VERSION 5.7 ;
  NOWIREEXTENSIONATPIN ON ;
  DIVIDERCHAR "/" ;
  BUSBITCHARS "[]" ;
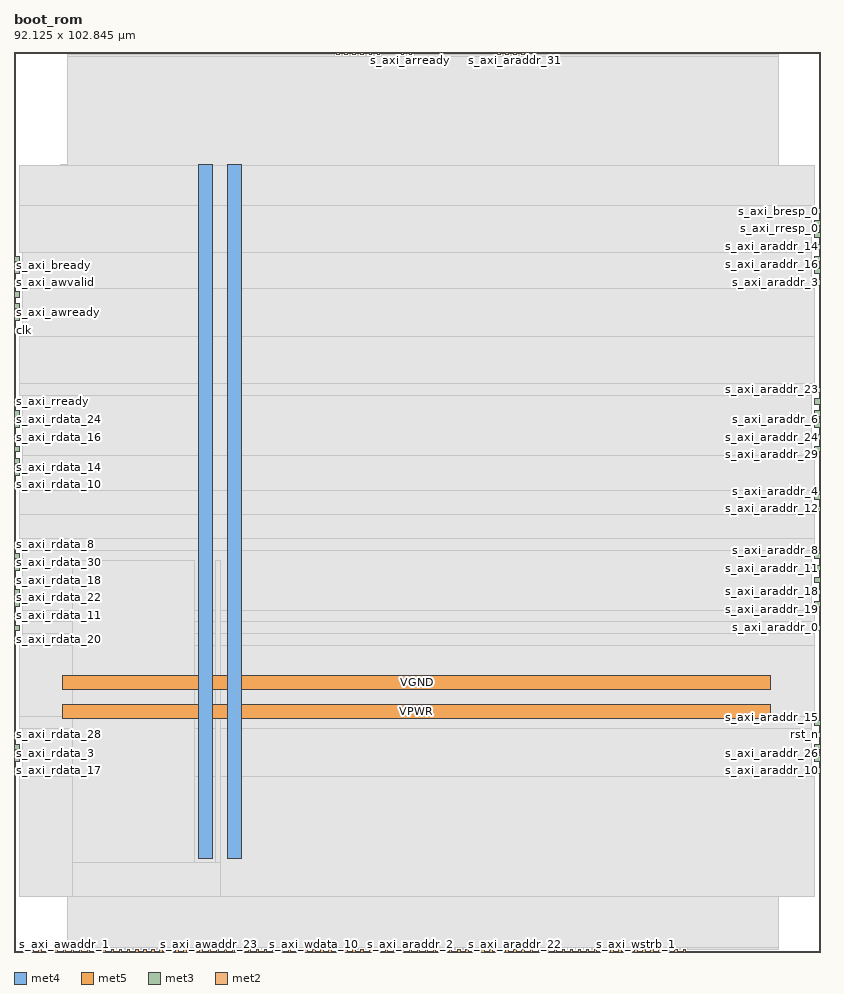
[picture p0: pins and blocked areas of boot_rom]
MACRO boot_rom
  CLASS BLOCK ;
  FOREIGN boot_rom ;
  ORIGIN 0.000 0.000 ;
  SIZE 92.125 BY 102.845 ;
  PIN VGND
    DIRECTION INOUT ;
    USE GROUND ;
    PORT
      LAYER met4 ;
        RECT 24.340 10.640 25.940 90.000 ;
    END
    PORT
      LAYER met5 ;
        RECT 5.520 30.030 86.480 31.630 ;
    END
  END VGND
  PIN VPWR
    DIRECTION INOUT ;
    USE POWER ;
    PORT
      LAYER met4 ;
        RECT 21.040 10.640 22.640 90.000 ;
    END
    PORT
      LAYER met5 ;
        RECT 5.520 26.730 86.480 28.330 ;
    END
  END VPWR
  PIN clk
    DIRECTION INPUT ;
    USE SIGNAL ;
    ANTENNAGATEAREA 1.286700 ;
    ANTENNADIFFAREA 0.434700 ;
    PORT
      LAYER met3 ;
        RECT 0.000 70.760 0.600 71.360 ;
    END
  END clk
  PIN rst_n
    DIRECTION INPUT ;
    USE SIGNAL ;
    ANTENNAGATEAREA 0.647700 ;
    ANTENNADIFFAREA 0.434700 ;
    PORT
      LAYER met3 ;
        RECT 91.525 24.520 92.125 25.120 ;
    END
  END rst_n
  PIN s_axi_araddr_0
    DIRECTION INPUT ;
    USE SIGNAL ;
    ANTENNAGATEAREA 0.647700 ;
    ANTENNADIFFAREA 0.434700 ;
    PORT
      LAYER met3 ;
        RECT 91.525 36.760 92.125 37.360 ;
    END
  END s_axi_araddr_0
  PIN s_axi_araddr_1
    DIRECTION INPUT ;
    USE SIGNAL ;
    ANTENNAGATEAREA 0.647700 ;
    ANTENNADIFFAREA 0.434700 ;
    PORT
      LAYER met2 ;
        RECT 56.210 102.565 56.490 102.845 ;
    END
  END s_axi_araddr_1
  PIN s_axi_araddr_10
    DIRECTION INPUT ;
    USE SIGNAL ;
    ANTENNAGATEAREA 0.647700 ;
    ANTENNADIFFAREA 0.434700 ;
    PORT
      LAYER met3 ;
        RECT 91.525 20.440 92.125 21.040 ;
    END
  END s_axi_araddr_10
  PIN s_axi_araddr_11
    DIRECTION INPUT ;
    USE SIGNAL ;
    ANTENNAGATEAREA 0.647700 ;
    ANTENNADIFFAREA 0.434700 ;
    PORT
      LAYER met3 ;
        RECT 91.525 43.560 92.125 44.160 ;
    END
  END s_axi_araddr_11
  PIN s_axi_araddr_12
    DIRECTION INPUT ;
    USE SIGNAL ;
    ANTENNAGATEAREA 0.647700 ;
    ANTENNADIFFAREA 0.434700 ;
    PORT
      LAYER met3 ;
        RECT 91.525 50.360 92.125 50.960 ;
    END
  END s_axi_araddr_12
  PIN s_axi_araddr_13
    DIRECTION INPUT ;
    USE SIGNAL ;
    ANTENNAGATEAREA 0.647700 ;
    ANTENNADIFFAREA 0.434700 ;
    PORT
      LAYER met2 ;
        RECT 56.210 0.000 56.490 0.280 ;
    END
  END s_axi_araddr_13
  PIN s_axi_araddr_14
    DIRECTION INPUT ;
    USE SIGNAL ;
    ANTENNAGATEAREA 0.647700 ;
    ANTENNADIFFAREA 0.434700 ;
    PORT
      LAYER met3 ;
        RECT 91.525 80.280 92.125 80.880 ;
    END
  END s_axi_araddr_14
  PIN s_axi_araddr_15
    DIRECTION INPUT ;
    USE SIGNAL ;
    ANTENNAGATEAREA 0.647700 ;
    ANTENNADIFFAREA 0.434700 ;
    PORT
      LAYER met3 ;
        RECT 91.525 25.880 92.125 26.480 ;
    END
  END s_axi_araddr_15
  PIN s_axi_araddr_16
    DIRECTION INPUT ;
    USE SIGNAL ;
    ANTENNAGATEAREA 0.647700 ;
    ANTENNADIFFAREA 0.434700 ;
    PORT
      LAYER met3 ;
        RECT 91.525 78.920 92.125 79.520 ;
    END
  END s_axi_araddr_16
  PIN s_axi_araddr_17
    DIRECTION INPUT ;
    USE SIGNAL ;
    ANTENNAGATEAREA 0.647700 ;
    ANTENNADIFFAREA 0.434700 ;
    PORT
      LAYER met2 ;
        RECT 55.290 102.565 55.570 102.845 ;
    END
  END s_axi_araddr_17
  PIN s_axi_araddr_18
    DIRECTION INPUT ;
    USE SIGNAL ;
    ANTENNAGATEAREA 0.647700 ;
    ANTENNADIFFAREA 0.434700 ;
    PORT
      LAYER met3 ;
        RECT 91.525 40.840 92.125 41.440 ;
    END
  END s_axi_araddr_18
  PIN s_axi_araddr_19
    DIRECTION INPUT ;
    USE SIGNAL ;
    ANTENNAGATEAREA 0.647700 ;
    ANTENNADIFFAREA 0.434700 ;
    PORT
      LAYER met3 ;
        RECT 91.525 39.480 92.125 40.080 ;
    END
  END s_axi_araddr_19
  PIN s_axi_araddr_2
    DIRECTION INPUT ;
    USE SIGNAL ;
    ANTENNAGATEAREA 0.647700 ;
    ANTENNADIFFAREA 0.434700 ;
    PORT
      LAYER met2 ;
        RECT 45.170 0.000 45.450 0.280 ;
    END
  END s_axi_araddr_2
  PIN s_axi_araddr_20
    DIRECTION INPUT ;
    USE SIGNAL ;
    ANTENNAGATEAREA 0.647700 ;
    ANTENNADIFFAREA 0.434700 ;
    PORT
      LAYER met3 ;
        RECT 91.525 77.560 92.125 78.160 ;
    END
  END s_axi_araddr_20
  PIN s_axi_araddr_21
    DIRECTION INPUT ;
    USE SIGNAL ;
    ANTENNAGATEAREA 0.647700 ;
    ANTENNADIFFAREA 0.434700 ;
    PORT
      LAYER met3 ;
        RECT 91.525 23.160 92.125 23.760 ;
    END
  END s_axi_araddr_21
  PIN s_axi_araddr_22
    DIRECTION INPUT ;
    USE SIGNAL ;
    ANTENNAGATEAREA 0.647700 ;
    ANTENNADIFFAREA 0.434700 ;
    PORT
      LAYER met2 ;
        RECT 57.130 0.000 57.410 0.280 ;
    END
  END s_axi_araddr_22
  PIN s_axi_araddr_23
    DIRECTION INPUT ;
    USE SIGNAL ;
    ANTENNAGATEAREA 0.647700 ;
    ANTENNADIFFAREA 0.434700 ;
    PORT
      LAYER met3 ;
        RECT 91.525 63.960 92.125 64.560 ;
    END
  END s_axi_araddr_23
  PIN s_axi_araddr_24
    DIRECTION INPUT ;
    USE SIGNAL ;
    ANTENNAGATEAREA 0.647700 ;
    ANTENNADIFFAREA 0.434700 ;
    PORT
      LAYER met3 ;
        RECT 91.525 58.520 92.125 59.120 ;
    END
  END s_axi_araddr_24
  PIN s_axi_araddr_25
    DIRECTION INPUT ;
    USE SIGNAL ;
    ANTENNAGATEAREA 0.647700 ;
    ANTENNADIFFAREA 0.434700 ;
    PORT
      LAYER met2 ;
        RECT 62.650 0.000 62.930 0.280 ;
    END
  END s_axi_araddr_25
  PIN s_axi_araddr_26
    DIRECTION INPUT ;
    USE SIGNAL ;
    ANTENNAGATEAREA 0.647700 ;
    ANTENNADIFFAREA 0.434700 ;
    PORT
      LAYER met3 ;
        RECT 91.525 21.800 92.125 22.400 ;
    END
  END s_axi_araddr_26
  PIN s_axi_araddr_27
    DIRECTION INPUT ;
    USE SIGNAL ;
    ANTENNAGATEAREA 0.647700 ;
    ANTENNADIFFAREA 0.434700 ;
    PORT
      LAYER met3 ;
        RECT 91.525 42.200 92.125 42.800 ;
    END
  END s_axi_araddr_27
  PIN s_axi_araddr_28
    DIRECTION INPUT ;
    USE SIGNAL ;
    ANTENNAGATEAREA 0.647700 ;
    ANTENNADIFFAREA 0.434700 ;
    PORT
      LAYER met2 ;
        RECT 55.290 0.000 55.570 0.280 ;
    END
  END s_axi_araddr_28
  PIN s_axi_araddr_29
    DIRECTION INPUT ;
    USE SIGNAL ;
    ANTENNAGATEAREA 0.647700 ;
    ANTENNADIFFAREA 0.434700 ;
    PORT
      LAYER met3 ;
        RECT 91.525 57.160 92.125 57.760 ;
    END
  END s_axi_araddr_29
  PIN s_axi_araddr_3
    DIRECTION INPUT ;
    USE SIGNAL ;
    ANTENNAGATEAREA 0.647700 ;
    ANTENNADIFFAREA 0.434700 ;
    PORT
      LAYER met3 ;
        RECT 91.525 76.200 92.125 76.800 ;
    END
  END s_axi_araddr_3
  PIN s_axi_araddr_30
    DIRECTION INPUT ;
    USE SIGNAL ;
    ANTENNAGATEAREA 0.647700 ;
    ANTENNADIFFAREA 0.434700 ;
    PORT
      LAYER met3 ;
        RECT 91.525 61.240 92.125 61.840 ;
    END
  END s_axi_araddr_30
  PIN s_axi_araddr_31
    DIRECTION INPUT ;
    USE SIGNAL ;
    ANTENNAGATEAREA 0.647700 ;
    ANTENNADIFFAREA 0.434700 ;
    PORT
      LAYER met2 ;
        RECT 57.130 102.565 57.410 102.845 ;
    END
  END s_axi_araddr_31
  PIN s_axi_araddr_4
    DIRECTION INPUT ;
    USE SIGNAL ;
    ANTENNAGATEAREA 0.647700 ;
    ANTENNADIFFAREA 0.434700 ;
    PORT
      LAYER met3 ;
        RECT 91.525 51.720 92.125 52.320 ;
    END
  END s_axi_araddr_4
  PIN s_axi_araddr_5
    DIRECTION INPUT ;
    USE SIGNAL ;
    ANTENNAGATEAREA 0.647700 ;
    ANTENNADIFFAREA 0.434700 ;
    PORT
      LAYER met2 ;
        RECT 59.890 0.000 60.170 0.280 ;
    END
  END s_axi_araddr_5
  PIN s_axi_araddr_6
    DIRECTION INPUT ;
    USE SIGNAL ;
    ANTENNAGATEAREA 0.647700 ;
    ANTENNADIFFAREA 0.434700 ;
    PORT
      LAYER met3 ;
        RECT 91.525 59.880 92.125 60.480 ;
    END
  END s_axi_araddr_6
  PIN s_axi_araddr_7
    DIRECTION INPUT ;
    USE SIGNAL ;
    ANTENNAGATEAREA 0.647700 ;
    ANTENNADIFFAREA 0.434700 ;
    PORT
      LAYER met3 ;
        RECT 91.525 62.600 92.125 63.200 ;
    END
  END s_axi_araddr_7
  PIN s_axi_araddr_8
    DIRECTION INPUT ;
    USE SIGNAL ;
    ANTENNAGATEAREA 0.647700 ;
    ANTENNADIFFAREA 0.434700 ;
    PORT
      LAYER met3 ;
        RECT 91.525 44.920 92.125 45.520 ;
    END
  END s_axi_araddr_8
  PIN s_axi_araddr_9
    DIRECTION INPUT ;
    USE SIGNAL ;
    ANTENNAGATEAREA 0.647700 ;
    ANTENNADIFFAREA 0.434700 ;
    PORT
      LAYER met2 ;
        RECT 58.050 102.565 58.330 102.845 ;
    END
  END s_axi_araddr_9
  PIN s_axi_arready
    DIRECTION OUTPUT ;
    USE SIGNAL ;
    ANTENNAGATEAREA 0.434700 ;
    ANTENNADIFFAREA 1.137600 ;
    PORT
      LAYER met2 ;
        RECT 45.170 102.565 45.450 102.845 ;
    END
  END s_axi_arready
  PIN s_axi_arvalid
    DIRECTION INPUT ;
    USE SIGNAL ;
    ANTENNAGATEAREA 0.647700 ;
    ANTENNADIFFAREA 0.434700 ;
    PORT
      LAYER met2 ;
        RECT 44.250 102.565 44.530 102.845 ;
    END
  END s_axi_arvalid
  PIN s_axi_awaddr_0
    DIRECTION INPUT ;
    USE SIGNAL ;
    PORT
      LAYER met2 ;
        RECT 2.850 0.000 3.130 0.280 ;
    END
  END s_axi_awaddr_0
  PIN s_axi_awaddr_1
    DIRECTION INPUT ;
    USE SIGNAL ;
    PORT
      LAYER met2 ;
        RECT 5.610 0.000 5.890 0.280 ;
    END
  END s_axi_awaddr_1
  PIN s_axi_awaddr_10
    DIRECTION INPUT ;
    USE SIGNAL ;
    PORT
      LAYER met2 ;
        RECT 4.690 0.000 4.970 0.280 ;
    END
  END s_axi_awaddr_10
  PIN s_axi_awaddr_11
    DIRECTION INPUT ;
    USE SIGNAL ;
    PORT
      LAYER met2 ;
        RECT 7.450 0.000 7.730 0.280 ;
    END
  END s_axi_awaddr_11
  PIN s_axi_awaddr_12
    DIRECTION INPUT ;
    USE SIGNAL ;
    PORT
      LAYER met2 ;
        RECT 6.530 0.000 6.810 0.280 ;
    END
  END s_axi_awaddr_12
  PIN s_axi_awaddr_13
    DIRECTION INPUT ;
    USE SIGNAL ;
    PORT
      LAYER met2 ;
        RECT 28.610 0.000 28.890 0.280 ;
    END
  END s_axi_awaddr_13
  PIN s_axi_awaddr_14
    DIRECTION INPUT ;
    USE SIGNAL ;
    PORT
      LAYER met2 ;
        RECT 8.370 0.000 8.650 0.280 ;
    END
  END s_axi_awaddr_14
  PIN s_axi_awaddr_15
    DIRECTION INPUT ;
    USE SIGNAL ;
    PORT
      LAYER met2 ;
        RECT 9.290 0.000 9.570 0.280 ;
    END
  END s_axi_awaddr_15
  PIN s_axi_awaddr_16
    DIRECTION INPUT ;
    USE SIGNAL ;
    PORT
      LAYER met2 ;
        RECT 10.210 0.000 10.490 0.280 ;
    END
  END s_axi_awaddr_16
  PIN s_axi_awaddr_17
    DIRECTION INPUT ;
    USE SIGNAL ;
    PORT
      LAYER met2 ;
        RECT 11.130 0.000 11.410 0.280 ;
    END
  END s_axi_awaddr_17
  PIN s_axi_awaddr_18
    DIRECTION INPUT ;
    USE SIGNAL ;
    PORT
      LAYER met2 ;
        RECT 12.050 0.000 12.330 0.280 ;
    END
  END s_axi_awaddr_18
  PIN s_axi_awaddr_19
    DIRECTION INPUT ;
    USE SIGNAL ;
    PORT
      LAYER met2 ;
        RECT 12.970 0.000 13.250 0.280 ;
    END
  END s_axi_awaddr_19
  PIN s_axi_awaddr_2
    DIRECTION INPUT ;
    USE SIGNAL ;
    PORT
      LAYER met2 ;
        RECT 13.890 0.000 14.170 0.280 ;
    END
  END s_axi_awaddr_2
  PIN s_axi_awaddr_20
    DIRECTION INPUT ;
    USE SIGNAL ;
    PORT
      LAYER met2 ;
        RECT 46.090 0.000 46.370 0.280 ;
    END
  END s_axi_awaddr_20
  PIN s_axi_awaddr_21
    DIRECTION INPUT ;
    USE SIGNAL ;
    PORT
      LAYER met2 ;
        RECT 14.810 0.000 15.090 0.280 ;
    END
  END s_axi_awaddr_21
  PIN s_axi_awaddr_22
    DIRECTION INPUT ;
    USE SIGNAL ;
    PORT
      LAYER met2 ;
        RECT 15.730 0.000 16.010 0.280 ;
    END
  END s_axi_awaddr_22
  PIN s_axi_awaddr_23
    DIRECTION INPUT ;
    USE SIGNAL ;
    PORT
      LAYER met2 ;
        RECT 22.170 0.000 22.450 0.280 ;
    END
  END s_axi_awaddr_23
  PIN s_axi_awaddr_24
    DIRECTION INPUT ;
    USE SIGNAL ;
    PORT
      LAYER met2 ;
        RECT 1.930 0.000 2.210 0.280 ;
    END
  END s_axi_awaddr_24
  PIN s_axi_awaddr_25
    DIRECTION INPUT ;
    USE SIGNAL ;
    PORT
      LAYER met2 ;
        RECT 18.490 0.000 18.770 0.280 ;
    END
  END s_axi_awaddr_25
  PIN s_axi_awaddr_26
    DIRECTION INPUT ;
    USE SIGNAL ;
    PORT
      LAYER met2 ;
        RECT 19.410 0.000 19.690 0.280 ;
    END
  END s_axi_awaddr_26
  PIN s_axi_awaddr_27
    DIRECTION INPUT ;
    USE SIGNAL ;
    PORT
      LAYER met2 ;
        RECT 20.330 0.000 20.610 0.280 ;
    END
  END s_axi_awaddr_27
  PIN s_axi_awaddr_28
    DIRECTION INPUT ;
    USE SIGNAL ;
    PORT
      LAYER met2 ;
        RECT 21.250 0.000 21.530 0.280 ;
    END
  END s_axi_awaddr_28
  PIN s_axi_awaddr_29
    DIRECTION INPUT ;
    USE SIGNAL ;
    PORT
      LAYER met2 ;
        RECT 27.690 0.000 27.970 0.280 ;
    END
  END s_axi_awaddr_29
  PIN s_axi_awaddr_3
    DIRECTION INPUT ;
    USE SIGNAL ;
    PORT
      LAYER met2 ;
        RECT 23.090 0.000 23.370 0.280 ;
    END
  END s_axi_awaddr_3
  PIN s_axi_awaddr_30
    DIRECTION INPUT ;
    USE SIGNAL ;
    PORT
      LAYER met2 ;
        RECT 24.010 0.000 24.290 0.280 ;
    END
  END s_axi_awaddr_30
  PIN s_axi_awaddr_31
    DIRECTION INPUT ;
    USE SIGNAL ;
    PORT
      LAYER met2 ;
        RECT 24.930 0.000 25.210 0.280 ;
    END
  END s_axi_awaddr_31
  PIN s_axi_awaddr_4
    DIRECTION INPUT ;
    USE SIGNAL ;
    PORT
      LAYER met2 ;
        RECT 25.850 0.000 26.130 0.280 ;
    END
  END s_axi_awaddr_4
  PIN s_axi_awaddr_5
    DIRECTION INPUT ;
    USE SIGNAL ;
    PORT
      LAYER met2 ;
        RECT 26.770 0.000 27.050 0.280 ;
    END
  END s_axi_awaddr_5
  PIN s_axi_awaddr_6
    DIRECTION INPUT ;
    USE SIGNAL ;
    PORT
      LAYER met2 ;
        RECT 33.210 0.000 33.490 0.280 ;
    END
  END s_axi_awaddr_6
  PIN s_axi_awaddr_7
    DIRECTION INPUT ;
    USE SIGNAL ;
    PORT
      LAYER met2 ;
        RECT 54.370 0.000 54.650 0.280 ;
    END
  END s_axi_awaddr_7
  PIN s_axi_awaddr_8
    DIRECTION INPUT ;
    USE SIGNAL ;
    PORT
      LAYER met2 ;
        RECT 29.530 0.000 29.810 0.280 ;
    END
  END s_axi_awaddr_8
  PIN s_axi_awaddr_9
    DIRECTION INPUT ;
    USE SIGNAL ;
    PORT
      LAYER met2 ;
        RECT 30.450 0.000 30.730 0.280 ;
    END
  END s_axi_awaddr_9
  PIN s_axi_awready
    DIRECTION OUTPUT ;
    USE SIGNAL ;
    ANTENNAGATEAREA 0.434700 ;
    ANTENNADIFFAREA 1.137600 ;
    PORT
      LAYER met3 ;
        RECT 0.000 72.120 0.600 72.720 ;
    END
  END s_axi_awready
  PIN s_axi_awvalid
    DIRECTION INPUT ;
    USE SIGNAL ;
    ANTENNAGATEAREA 0.647700 ;
    ANTENNADIFFAREA 0.434700 ;
    PORT
      LAYER met3 ;
        RECT 0.000 76.200 0.600 76.800 ;
    END
  END s_axi_awvalid
  PIN s_axi_bready
    DIRECTION INPUT ;
    USE SIGNAL ;
    ANTENNAGATEAREA 0.647700 ;
    ANTENNADIFFAREA 0.434700 ;
    PORT
      LAYER met3 ;
        RECT 0.000 77.560 0.600 78.160 ;
    END
  END s_axi_bready
  PIN s_axi_bresp_0
    DIRECTION OUTPUT ;
    USE SIGNAL ;
    ANTENNAGATEAREA 0.434700 ;
    ANTENNADIFFAREA 0.434700 ;
    PORT
      LAYER met3 ;
        RECT 91.525 84.360 92.125 84.960 ;
    END
  END s_axi_bresp_0
  PIN s_axi_bresp_1
    DIRECTION OUTPUT ;
    USE SIGNAL ;
    PORT
      LAYER met2 ;
        RECT 31.370 0.000 31.650 0.280 ;
    END
  END s_axi_bresp_1
  PIN s_axi_bvalid
    DIRECTION OUTPUT ;
    USE SIGNAL ;
    ANTENNAGATEAREA 0.434700 ;
    ANTENNADIFFAREA 1.137600 ;
    PORT
      LAYER met3 ;
        RECT 0.000 78.920 0.600 79.520 ;
    END
  END s_axi_bvalid
  PIN s_axi_rdata_0
    DIRECTION OUTPUT ;
    USE SIGNAL ;
    ANTENNAGATEAREA 0.434700 ;
    ANTENNADIFFAREA 1.137600 ;
    PORT
      LAYER met2 ;
        RECT 37.810 102.565 38.090 102.845 ;
    END
  END s_axi_rdata_0
  PIN s_axi_rdata_1
    DIRECTION OUTPUT ;
    USE SIGNAL ;
    ANTENNAGATEAREA 0.434700 ;
    ANTENNADIFFAREA 1.137600 ;
    PORT
      LAYER met2 ;
        RECT 39.650 102.565 39.930 102.845 ;
    END
  END s_axi_rdata_1
  PIN s_axi_rdata_10
    DIRECTION OUTPUT ;
    USE SIGNAL ;
    ANTENNAGATEAREA 0.434700 ;
    ANTENNADIFFAREA 1.137600 ;
    PORT
      LAYER met3 ;
        RECT 0.000 53.080 0.600 53.680 ;
    END
  END s_axi_rdata_10
  PIN s_axi_rdata_11
    DIRECTION OUTPUT ;
    USE SIGNAL ;
    ANTENNAGATEAREA 0.434700 ;
    ANTENNADIFFAREA 1.137600 ;
    PORT
      LAYER met3 ;
        RECT 0.000 38.120 0.600 38.720 ;
    END
  END s_axi_rdata_11
  PIN s_axi_rdata_12
    DIRECTION OUTPUT ;
    USE SIGNAL ;
    ANTENNAGATEAREA 0.434700 ;
    ANTENNADIFFAREA 1.137600 ;
    PORT
      LAYER met2 ;
        RECT 16.650 0.000 16.930 0.280 ;
    END
  END s_axi_rdata_12
  PIN s_axi_rdata_13
    DIRECTION OUTPUT ;
    USE SIGNAL ;
    ANTENNAGATEAREA 0.434700 ;
    ANTENNADIFFAREA 1.137600 ;
    PORT
      LAYER met3 ;
        RECT 0.000 61.240 0.600 61.840 ;
    END
  END s_axi_rdata_13
  PIN s_axi_rdata_14
    DIRECTION OUTPUT ;
    USE SIGNAL ;
    ANTENNAGATEAREA 0.434700 ;
    ANTENNADIFFAREA 1.137600 ;
    PORT
      LAYER met3 ;
        RECT 0.000 54.440 0.600 55.040 ;
    END
  END s_axi_rdata_14
  PIN s_axi_rdata_15
    DIRECTION OUTPUT ;
    USE SIGNAL ;
    ANTENNAGATEAREA 0.434700 ;
    ANTENNADIFFAREA 1.137600 ;
    PORT
      LAYER met2 ;
        RECT 38.730 0.000 39.010 0.280 ;
    END
  END s_axi_rdata_15
  PIN s_axi_rdata_16
    DIRECTION OUTPUT ;
    USE SIGNAL ;
    ANTENNAGATEAREA 0.434700 ;
    ANTENNADIFFAREA 1.137600 ;
    PORT
      LAYER met3 ;
        RECT 0.000 58.520 0.600 59.120 ;
    END
  END s_axi_rdata_16
  PIN s_axi_rdata_17
    DIRECTION OUTPUT ;
    USE SIGNAL ;
    ANTENNAGATEAREA 0.434700 ;
    ANTENNADIFFAREA 1.137600 ;
    PORT
      LAYER met3 ;
        RECT 0.000 20.440 0.600 21.040 ;
    END
  END s_axi_rdata_17
  PIN s_axi_rdata_18
    DIRECTION OUTPUT ;
    USE SIGNAL ;
    ANTENNAGATEAREA 0.434700 ;
    ANTENNADIFFAREA 1.137600 ;
    PORT
      LAYER met3 ;
        RECT 0.000 42.200 0.600 42.800 ;
    END
  END s_axi_rdata_18
  PIN s_axi_rdata_19
    DIRECTION OUTPUT ;
    USE SIGNAL ;
    ANTENNAGATEAREA 0.434700 ;
    ANTENNADIFFAREA 1.137600 ;
    PORT
      LAYER met2 ;
        RECT 40.570 0.000 40.850 0.280 ;
    END
  END s_axi_rdata_19
  PIN s_axi_rdata_2
    DIRECTION OUTPUT ;
    USE SIGNAL ;
    ANTENNAGATEAREA 0.434700 ;
    ANTENNADIFFAREA 1.137600 ;
    PORT
      LAYER met2 ;
        RECT 38.730 102.565 39.010 102.845 ;
    END
  END s_axi_rdata_2
  PIN s_axi_rdata_20
    DIRECTION OUTPUT ;
    USE SIGNAL ;
    ANTENNAGATEAREA 0.434700 ;
    ANTENNADIFFAREA 1.137600 ;
    PORT
      LAYER met3 ;
        RECT 0.000 35.400 0.600 36.000 ;
    END
  END s_axi_rdata_20
  PIN s_axi_rdata_21
    DIRECTION OUTPUT ;
    USE SIGNAL ;
    ANTENNAGATEAREA 0.434700 ;
    ANTENNADIFFAREA 1.137600 ;
    PORT
      LAYER met3 ;
        RECT 0.000 57.160 0.600 57.760 ;
    END
  END s_axi_rdata_21
  PIN s_axi_rdata_22
    DIRECTION OUTPUT ;
    USE SIGNAL ;
    ANTENNAGATEAREA 0.434700 ;
    ANTENNADIFFAREA 1.137600 ;
    PORT
      LAYER met3 ;
        RECT 0.000 40.840 0.600 41.440 ;
    END
  END s_axi_rdata_22
  PIN s_axi_rdata_23
    DIRECTION OUTPUT ;
    USE SIGNAL ;
    ANTENNAGATEAREA 0.434700 ;
    ANTENNADIFFAREA 1.137600 ;
    PORT
      LAYER met2 ;
        RECT 17.570 0.000 17.850 0.280 ;
    END
  END s_axi_rdata_23
  PIN s_axi_rdata_24
    DIRECTION OUTPUT ;
    USE SIGNAL ;
    ANTENNAGATEAREA 0.434700 ;
    ANTENNADIFFAREA 1.137600 ;
    PORT
      LAYER met3 ;
        RECT 0.000 59.880 0.600 60.480 ;
    END
  END s_axi_rdata_24
  PIN s_axi_rdata_25
    DIRECTION OUTPUT ;
    USE SIGNAL ;
    ANTENNAGATEAREA 0.434700 ;
    ANTENNADIFFAREA 1.137600 ;
    PORT
      LAYER met3 ;
        RECT 0.000 39.480 0.600 40.080 ;
    END
  END s_axi_rdata_25
  PIN s_axi_rdata_26
    DIRECTION OUTPUT ;
    USE SIGNAL ;
    ANTENNAGATEAREA 0.434700 ;
    ANTENNADIFFAREA 1.137600 ;
    PORT
      LAYER met3 ;
        RECT 0.000 44.920 0.600 45.520 ;
    END
  END s_axi_rdata_26
  PIN s_axi_rdata_27
    DIRECTION OUTPUT ;
    USE SIGNAL ;
    ANTENNAGATEAREA 0.434700 ;
    ANTENNADIFFAREA 1.137600 ;
    PORT
      LAYER met3 ;
        RECT 0.000 55.800 0.600 56.400 ;
    END
  END s_axi_rdata_27
  PIN s_axi_rdata_28
    DIRECTION OUTPUT ;
    USE SIGNAL ;
    ANTENNAGATEAREA 0.434700 ;
    ANTENNADIFFAREA 1.137600 ;
    PORT
      LAYER met3 ;
        RECT 0.000 24.520 0.600 25.120 ;
    END
  END s_axi_rdata_28
  PIN s_axi_rdata_29
    DIRECTION OUTPUT ;
    USE SIGNAL ;
    ANTENNAGATEAREA 0.434700 ;
    ANTENNADIFFAREA 1.137600 ;
    PORT
      LAYER met2 ;
        RECT 37.810 0.000 38.090 0.280 ;
    END
  END s_axi_rdata_29
  PIN s_axi_rdata_3
    DIRECTION OUTPUT ;
    USE SIGNAL ;
    ANTENNAGATEAREA 0.434700 ;
    ANTENNADIFFAREA 1.137600 ;
    PORT
      LAYER met3 ;
        RECT 0.000 21.800 0.600 22.400 ;
    END
  END s_axi_rdata_3
  PIN s_axi_rdata_30
    DIRECTION OUTPUT ;
    USE SIGNAL ;
    ANTENNAGATEAREA 0.434700 ;
    ANTENNADIFFAREA 1.137600 ;
    PORT
      LAYER met3 ;
        RECT 0.000 43.560 0.600 44.160 ;
    END
  END s_axi_rdata_30
  PIN s_axi_rdata_31
    DIRECTION OUTPUT ;
    USE SIGNAL ;
    ANTENNAGATEAREA 0.434700 ;
    ANTENNADIFFAREA 1.137600 ;
    PORT
      LAYER met3 ;
        RECT 0.000 23.160 0.600 23.760 ;
    END
  END s_axi_rdata_31
  PIN s_axi_rdata_4
    DIRECTION OUTPUT ;
    USE SIGNAL ;
    ANTENNAGATEAREA 0.434700 ;
    ANTENNADIFFAREA 1.137600 ;
    PORT
      LAYER met2 ;
        RECT 36.890 0.000 37.170 0.280 ;
    END
  END s_axi_rdata_4
  PIN s_axi_rdata_5
    DIRECTION OUTPUT ;
    USE SIGNAL ;
    ANTENNAGATEAREA 0.434700 ;
    ANTENNADIFFAREA 1.137600 ;
    PORT
      LAYER met2 ;
        RECT 40.570 102.565 40.850 102.845 ;
    END
  END s_axi_rdata_5
  PIN s_axi_rdata_6
    DIRECTION OUTPUT ;
    USE SIGNAL ;
    ANTENNAGATEAREA 0.434700 ;
    ANTENNADIFFAREA 1.137600 ;
    PORT
      LAYER met2 ;
        RECT 39.650 0.000 39.930 0.280 ;
    END
  END s_axi_rdata_6
  PIN s_axi_rdata_7
    DIRECTION OUTPUT ;
    USE SIGNAL ;
    ANTENNAGATEAREA 0.434700 ;
    ANTENNADIFFAREA 1.137600 ;
    PORT
      LAYER met2 ;
        RECT 41.490 102.565 41.770 102.845 ;
    END
  END s_axi_rdata_7
  PIN s_axi_rdata_8
    DIRECTION OUTPUT ;
    USE SIGNAL ;
    ANTENNAGATEAREA 0.434700 ;
    ANTENNADIFFAREA 1.137600 ;
    PORT
      LAYER met3 ;
        RECT 0.000 46.280 0.600 46.880 ;
    END
  END s_axi_rdata_8
  PIN s_axi_rdata_9
    DIRECTION OUTPUT ;
    USE SIGNAL ;
    ANTENNAGATEAREA 0.434700 ;
    ANTENNADIFFAREA 1.137600 ;
    PORT
      LAYER met3 ;
        RECT 0.000 36.760 0.600 37.360 ;
    END
  END s_axi_rdata_9
  PIN s_axi_rready
    DIRECTION INPUT ;
    USE SIGNAL ;
    ANTENNAGATEAREA 0.647700 ;
    ANTENNADIFFAREA 0.434700 ;
    PORT
      LAYER met3 ;
        RECT 0.000 62.600 0.600 63.200 ;
    END
  END s_axi_rready
  PIN s_axi_rresp_0
    DIRECTION OUTPUT ;
    USE SIGNAL ;
    ANTENNAGATEAREA 0.434700 ;
    ANTENNADIFFAREA 0.775300 ;
    PORT
      LAYER met3 ;
        RECT 91.525 83.000 92.125 83.600 ;
    END
  END s_axi_rresp_0
  PIN s_axi_rresp_1
    DIRECTION OUTPUT ;
    USE SIGNAL ;
    ANTENNAGATEAREA 0.434700 ;
    ANTENNADIFFAREA 0.775300 ;
    PORT
      LAYER met3 ;
        RECT 91.525 81.640 92.125 82.240 ;
    END
  END s_axi_rresp_1
  PIN s_axi_rvalid
    DIRECTION OUTPUT ;
    USE SIGNAL ;
    ANTENNAGATEAREA 0.434700 ;
    ANTENNADIFFAREA 1.137600 ;
    PORT
      LAYER met2 ;
        RECT 36.890 102.565 37.170 102.845 ;
    END
  END s_axi_rvalid
  PIN s_axi_wdata_0
    DIRECTION INPUT ;
    USE SIGNAL ;
    PORT
      LAYER met2 ;
        RECT 32.290 0.000 32.570 0.280 ;
    END
  END s_axi_wdata_0
  PIN s_axi_wdata_1
    DIRECTION INPUT ;
    USE SIGNAL ;
    PORT
      LAYER met2 ;
        RECT 42.410 0.000 42.690 0.280 ;
    END
  END s_axi_wdata_1
  PIN s_axi_wdata_10
    DIRECTION INPUT ;
    USE SIGNAL ;
    PORT
      LAYER met2 ;
        RECT 34.130 0.000 34.410 0.280 ;
    END
  END s_axi_wdata_10
  PIN s_axi_wdata_11
    DIRECTION INPUT ;
    USE SIGNAL ;
    PORT
      LAYER met2 ;
        RECT 35.050 0.000 35.330 0.280 ;
    END
  END s_axi_wdata_11
  PIN s_axi_wdata_12
    DIRECTION INPUT ;
    USE SIGNAL ;
    PORT
      LAYER met2 ;
        RECT 35.970 0.000 36.250 0.280 ;
    END
  END s_axi_wdata_12
  PIN s_axi_wdata_13
    DIRECTION INPUT ;
    USE SIGNAL ;
    PORT
      LAYER met2 ;
        RECT 76.450 0.000 76.730 0.280 ;
    END
  END s_axi_wdata_13
  PIN s_axi_wdata_14
    DIRECTION INPUT ;
    USE SIGNAL ;
    PORT
      LAYER met2 ;
        RECT 41.490 0.000 41.770 0.280 ;
    END
  END s_axi_wdata_14
  PIN s_axi_wdata_15
    DIRECTION INPUT ;
    USE SIGNAL ;
    PORT
      LAYER met2 ;
        RECT 47.930 0.000 48.210 0.280 ;
    END
  END s_axi_wdata_15
  PIN s_axi_wdata_16
    DIRECTION INPUT ;
    USE SIGNAL ;
    PORT
      LAYER met2 ;
        RECT 43.330 0.000 43.610 0.280 ;
    END
  END s_axi_wdata_16
  PIN s_axi_wdata_17
    DIRECTION INPUT ;
    USE SIGNAL ;
    PORT
      LAYER met2 ;
        RECT 44.250 0.000 44.530 0.280 ;
    END
  END s_axi_wdata_17
  PIN s_axi_wdata_18
    DIRECTION INPUT ;
    USE SIGNAL ;
    PORT
      LAYER met2 ;
        RECT 74.610 0.000 74.890 0.280 ;
    END
  END s_axi_wdata_18
  PIN s_axi_wdata_19
    DIRECTION INPUT ;
    USE SIGNAL ;
    PORT
      LAYER met2 ;
        RECT 47.010 0.000 47.290 0.280 ;
    END
  END s_axi_wdata_19
  PIN s_axi_wdata_2
    DIRECTION INPUT ;
    USE SIGNAL ;
    PORT
      LAYER met2 ;
        RECT 52.530 0.000 52.810 0.280 ;
    END
  END s_axi_wdata_2
  PIN s_axi_wdata_20
    DIRECTION INPUT ;
    USE SIGNAL ;
    PORT
      LAYER met2 ;
        RECT 48.850 0.000 49.130 0.280 ;
    END
  END s_axi_wdata_20
  PIN s_axi_wdata_21
    DIRECTION INPUT ;
    USE SIGNAL ;
    PORT
      LAYER met2 ;
        RECT 49.770 0.000 50.050 0.280 ;
    END
  END s_axi_wdata_21
  PIN s_axi_wdata_22
    DIRECTION INPUT ;
    USE SIGNAL ;
    PORT
      LAYER met2 ;
        RECT 50.690 0.000 50.970 0.280 ;
    END
  END s_axi_wdata_22
  PIN s_axi_wdata_23
    DIRECTION INPUT ;
    USE SIGNAL ;
    PORT
      LAYER met2 ;
        RECT 51.610 0.000 51.890 0.280 ;
    END
  END s_axi_wdata_23
  PIN s_axi_wdata_24
    DIRECTION INPUT ;
    USE SIGNAL ;
    PORT
      LAYER met2 ;
        RECT 58.050 0.000 58.330 0.280 ;
    END
  END s_axi_wdata_24
  PIN s_axi_wdata_25
    DIRECTION INPUT ;
    USE SIGNAL ;
    PORT
      LAYER met2 ;
        RECT 53.450 0.000 53.730 0.280 ;
    END
  END s_axi_wdata_25
  PIN s_axi_wdata_26
    DIRECTION INPUT ;
    USE SIGNAL ;
    PORT
      LAYER met2 ;
        RECT 75.530 0.000 75.810 0.280 ;
    END
  END s_axi_wdata_26
  PIN s_axi_wdata_27
    DIRECTION INPUT ;
    USE SIGNAL ;
    PORT
      LAYER met2 ;
        RECT 3.770 0.000 4.050 0.280 ;
    END
  END s_axi_wdata_27
  PIN s_axi_wdata_28
    DIRECTION INPUT ;
    USE SIGNAL ;
    PORT
      LAYER met2 ;
        RECT 61.730 0.000 62.010 0.280 ;
    END
  END s_axi_wdata_28
  PIN s_axi_wdata_29
    DIRECTION INPUT ;
    USE SIGNAL ;
    PORT
      LAYER met2 ;
        RECT 58.970 0.000 59.250 0.280 ;
    END
  END s_axi_wdata_29
  PIN s_axi_wdata_3
    DIRECTION INPUT ;
    USE SIGNAL ;
    PORT
      LAYER met2 ;
        RECT 60.810 0.000 61.090 0.280 ;
    END
  END s_axi_wdata_3
  PIN s_axi_wdata_30
    DIRECTION INPUT ;
    USE SIGNAL ;
    PORT
      LAYER met2 ;
        RECT 64.490 0.000 64.770 0.280 ;
    END
  END s_axi_wdata_30
  PIN s_axi_wdata_31
    DIRECTION INPUT ;
    USE SIGNAL ;
    PORT
      LAYER met2 ;
        RECT 63.570 0.000 63.850 0.280 ;
    END
  END s_axi_wdata_31
  PIN s_axi_wdata_4
    DIRECTION INPUT ;
    USE SIGNAL ;
    PORT
      LAYER met2 ;
        RECT 66.330 0.000 66.610 0.280 ;
    END
  END s_axi_wdata_4
  PIN s_axi_wdata_5
    DIRECTION INPUT ;
    USE SIGNAL ;
    PORT
      LAYER met2 ;
        RECT 65.410 0.000 65.690 0.280 ;
    END
  END s_axi_wdata_5
  PIN s_axi_wdata_6
    DIRECTION INPUT ;
    USE SIGNAL ;
    PORT
      LAYER met2 ;
        RECT 68.170 0.000 68.450 0.280 ;
    END
  END s_axi_wdata_6
  PIN s_axi_wdata_7
    DIRECTION INPUT ;
    USE SIGNAL ;
    PORT
      LAYER met2 ;
        RECT 67.250 0.000 67.530 0.280 ;
    END
  END s_axi_wdata_7
  PIN s_axi_wdata_8
    DIRECTION INPUT ;
    USE SIGNAL ;
    PORT
      LAYER met2 ;
        RECT 70.010 0.000 70.290 0.280 ;
    END
  END s_axi_wdata_8
  PIN s_axi_wdata_9
    DIRECTION INPUT ;
    USE SIGNAL ;
    PORT
      LAYER met2 ;
        RECT 69.090 0.000 69.370 0.280 ;
    END
  END s_axi_wdata_9
  PIN s_axi_wready
    DIRECTION OUTPUT ;
    USE SIGNAL ;
    ANTENNAGATEAREA 0.434700 ;
    ANTENNADIFFAREA 1.137600 ;
    PORT
      LAYER met3 ;
        RECT 0.000 73.480 0.600 74.080 ;
    END
  END s_axi_wready
  PIN s_axi_wstrb_0
    DIRECTION INPUT ;
    USE SIGNAL ;
    PORT
      LAYER met2 ;
        RECT 71.850 0.000 72.130 0.280 ;
    END
  END s_axi_wstrb_0
  PIN s_axi_wstrb_1
    DIRECTION INPUT ;
    USE SIGNAL ;
    PORT
      LAYER met2 ;
        RECT 70.930 0.000 71.210 0.280 ;
    END
  END s_axi_wstrb_1
  PIN s_axi_wstrb_2
    DIRECTION INPUT ;
    USE SIGNAL ;
    PORT
      LAYER met2 ;
        RECT 73.690 0.000 73.970 0.280 ;
    END
  END s_axi_wstrb_2
  PIN s_axi_wstrb_3
    DIRECTION INPUT ;
    USE SIGNAL ;
    PORT
      LAYER met2 ;
        RECT 72.770 0.000 73.050 0.280 ;
    END
  END s_axi_wstrb_3
  PIN s_axi_wvalid
    DIRECTION INPUT ;
    USE SIGNAL ;
    ANTENNAGATEAREA 0.647700 ;
    ANTENNADIFFAREA 0.434700 ;
    PORT
      LAYER met3 ;
        RECT 0.000 74.840 0.600 75.440 ;
    END
  END s_axi_wvalid
  OBS
      LAYER nwell ;
        RECT 5.330 10.795 86.670 89.950 ;
      LAYER li1 ;
        RECT 5.520 10.795 86.480 89.845 ;
      LAYER met1 ;
        RECT 5.520 8.200 87.330 90.000 ;
      LAYER met2 ;
        RECT 6.070 102.285 36.610 102.565 ;
        RECT 37.450 102.285 37.530 102.565 ;
        RECT 38.370 102.285 38.450 102.565 ;
        RECT 39.290 102.285 39.370 102.565 ;
        RECT 40.210 102.285 40.290 102.565 ;
        RECT 41.130 102.285 41.210 102.565 ;
        RECT 42.050 102.285 43.970 102.565 ;
        RECT 44.810 102.285 44.890 102.565 ;
        RECT 45.730 102.285 55.010 102.565 ;
        RECT 55.850 102.285 55.930 102.565 ;
        RECT 56.770 102.285 56.850 102.565 ;
        RECT 57.690 102.285 57.770 102.565 ;
        RECT 58.610 102.285 87.310 102.565 ;
        RECT 6.070 0.560 87.310 102.285 ;
        RECT 6.170 0.280 6.250 0.560 ;
        RECT 7.090 0.280 7.170 0.560 ;
        RECT 8.010 0.280 8.090 0.560 ;
        RECT 8.930 0.280 9.010 0.560 ;
        RECT 9.850 0.280 9.930 0.560 ;
        RECT 10.770 0.280 10.850 0.560 ;
        RECT 11.690 0.280 11.770 0.560 ;
        RECT 12.610 0.280 12.690 0.560 ;
        RECT 13.530 0.280 13.610 0.560 ;
        RECT 14.450 0.280 14.530 0.560 ;
        RECT 15.370 0.280 15.450 0.560 ;
        RECT 16.290 0.280 16.370 0.560 ;
        RECT 17.210 0.280 17.290 0.560 ;
        RECT 18.130 0.280 18.210 0.560 ;
        RECT 19.050 0.280 19.130 0.560 ;
        RECT 19.970 0.280 20.050 0.560 ;
        RECT 20.890 0.280 20.970 0.560 ;
        RECT 21.810 0.280 21.890 0.560 ;
        RECT 22.730 0.280 22.810 0.560 ;
        RECT 23.650 0.280 23.730 0.560 ;
        RECT 24.570 0.280 24.650 0.560 ;
        RECT 25.490 0.280 25.570 0.560 ;
        RECT 26.410 0.280 26.490 0.560 ;
        RECT 27.330 0.280 27.410 0.560 ;
        RECT 28.250 0.280 28.330 0.560 ;
        RECT 29.170 0.280 29.250 0.560 ;
        RECT 30.090 0.280 30.170 0.560 ;
        RECT 31.010 0.280 31.090 0.560 ;
        RECT 31.930 0.280 32.010 0.560 ;
        RECT 32.850 0.280 32.930 0.560 ;
        RECT 33.770 0.280 33.850 0.560 ;
        RECT 34.690 0.280 34.770 0.560 ;
        RECT 35.610 0.280 35.690 0.560 ;
        RECT 36.530 0.280 36.610 0.560 ;
        RECT 37.450 0.280 37.530 0.560 ;
        RECT 38.370 0.280 38.450 0.560 ;
        RECT 39.290 0.280 39.370 0.560 ;
        RECT 40.210 0.280 40.290 0.560 ;
        RECT 41.130 0.280 41.210 0.560 ;
        RECT 42.050 0.280 42.130 0.560 ;
        RECT 42.970 0.280 43.050 0.560 ;
        RECT 43.890 0.280 43.970 0.560 ;
        RECT 44.810 0.280 44.890 0.560 ;
        RECT 45.730 0.280 45.810 0.560 ;
        RECT 46.650 0.280 46.730 0.560 ;
        RECT 47.570 0.280 47.650 0.560 ;
        RECT 48.490 0.280 48.570 0.560 ;
        RECT 49.410 0.280 49.490 0.560 ;
        RECT 50.330 0.280 50.410 0.560 ;
        RECT 51.250 0.280 51.330 0.560 ;
        RECT 52.170 0.280 52.250 0.560 ;
        RECT 53.090 0.280 53.170 0.560 ;
        RECT 54.010 0.280 54.090 0.560 ;
        RECT 54.930 0.280 55.010 0.560 ;
        RECT 55.850 0.280 55.930 0.560 ;
        RECT 56.770 0.280 56.850 0.560 ;
        RECT 57.690 0.280 57.770 0.560 ;
        RECT 58.610 0.280 58.690 0.560 ;
        RECT 59.530 0.280 59.610 0.560 ;
        RECT 60.450 0.280 60.530 0.560 ;
        RECT 61.370 0.280 61.450 0.560 ;
        RECT 62.290 0.280 62.370 0.560 ;
        RECT 63.210 0.280 63.290 0.560 ;
        RECT 64.130 0.280 64.210 0.560 ;
        RECT 65.050 0.280 65.130 0.560 ;
        RECT 65.970 0.280 66.050 0.560 ;
        RECT 66.890 0.280 66.970 0.560 ;
        RECT 67.810 0.280 67.890 0.560 ;
        RECT 68.730 0.280 68.810 0.560 ;
        RECT 69.650 0.280 69.730 0.560 ;
        RECT 70.570 0.280 70.650 0.560 ;
        RECT 71.490 0.280 71.570 0.560 ;
        RECT 72.410 0.280 72.490 0.560 ;
        RECT 73.330 0.280 73.410 0.560 ;
        RECT 74.250 0.280 74.330 0.560 ;
        RECT 75.170 0.280 75.250 0.560 ;
        RECT 76.090 0.280 76.170 0.560 ;
        RECT 77.010 0.280 87.310 0.560 ;
      LAYER met3 ;
        RECT 0.600 85.360 91.525 89.925 ;
        RECT 0.600 79.920 91.125 85.360 ;
        RECT 1.000 75.800 91.125 79.920 ;
        RECT 1.000 70.360 91.525 75.800 ;
        RECT 0.600 64.960 91.525 70.360 ;
        RECT 0.600 63.600 91.125 64.960 ;
        RECT 1.000 56.760 91.125 63.600 ;
        RECT 1.000 52.720 91.525 56.760 ;
        RECT 1.000 52.680 91.125 52.720 ;
        RECT 0.600 49.960 91.125 52.680 ;
        RECT 0.600 47.280 91.525 49.960 ;
        RECT 1.000 45.920 91.525 47.280 ;
        RECT 1.000 39.080 91.125 45.920 ;
        RECT 1.000 37.760 91.525 39.080 ;
        RECT 1.000 36.360 91.125 37.760 ;
        RECT 1.000 35.000 91.525 36.360 ;
        RECT 0.600 26.880 91.525 35.000 ;
        RECT 0.600 25.520 91.125 26.880 ;
        RECT 1.000 20.040 91.125 25.520 ;
        RECT 0.600 6.295 91.525 20.040 ;
      LAYER met4 ;
        RECT 6.735 10.240 20.640 44.705 ;
        RECT 23.040 10.240 23.625 44.705 ;
        RECT 6.735 6.295 23.625 10.240 ;
  END
END boot_rom
END LIBRARY

